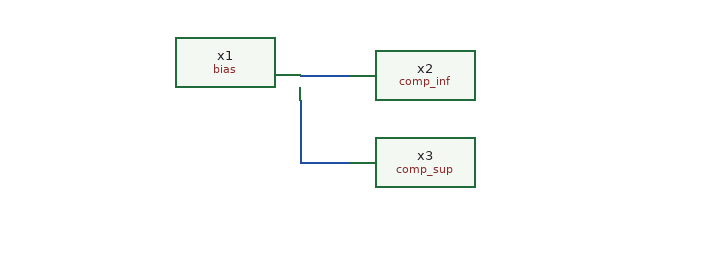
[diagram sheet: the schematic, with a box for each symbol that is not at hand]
v {xschem version=3.4.8RC file_version=1.3}
G {}
K {}
V {}
S {}
F {}
E {}
N -190 -50 -150 -50 {lab=#net1}
N -190 -30 -190 20 {lab=#net2}
N -190 20 -150 20 {lab=#net2}
C {bias.sym} -340 -40 0 0 {name=x1 VDD=VDD VSS=VSS}
C {comp_inf.sym} 0 -30 0 0 {name=x2 VDD=VDD VSS=VSS}
C {comp_sup.sym} 0 40 0 0 {name=x3 VDD=VDD VSS=VSS}
